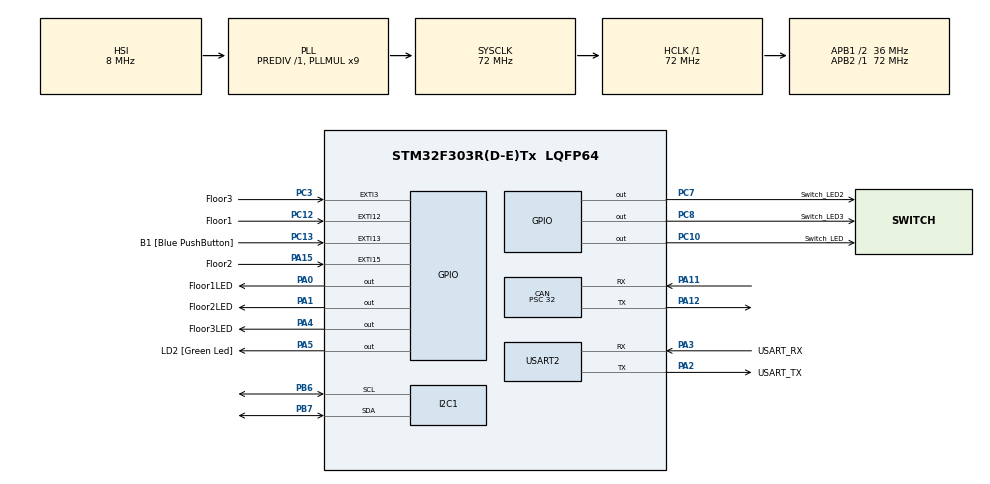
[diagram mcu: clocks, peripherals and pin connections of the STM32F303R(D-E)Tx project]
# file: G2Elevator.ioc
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CAN.BS1=CAN_BS1_4TQ
CAN.BS2=CAN_BS2_4TQ
CAN.CalculateBaudRate=125000
CAN.CalculateTimeBit=8000
CAN.CalculateTimeQuantum=888.8888888888889
CAN.Prescaler=32
Mcu.Family=STM32F3
Mcu.Name=STM32F303R(D-E)Tx
Mcu.Package=LQFP64
NVIC.EXTI15_10_IRQn=true\:0\:0\:false\:false\:true\:true\:true\:true
NVIC.PriorityGroup=NVIC_PRIORITYGROUP_0
NVIC.USB_LP_CAN_RX0_IRQn=true\:0\:0\:false\:false\:true\:true\:true\:true
PA0.GPIO_Label=Floor1LED
PA0.PinState=GPIO_PIN_RESET
PA0.Signal=GPIO_Output
PA1.GPIO_Label=Floor2LED
PA1.PinState=GPIO_PIN_RESET
PA1.Signal=GPIO_Output
PA11.Mode=CAN_Activate
PA11.Signal=CAN_RX
PA12.Mode=CAN_Activate
PA12.Signal=CAN_TX
PA13.GPIO_Label=TMS
PA13.Mode=Serial_Wire
PA13.Signal=SYS_JTMS-SWDIO
PA14.GPIO_Label=TCK
PA14.Mode=Serial_Wire
PA14.Signal=SYS_JTCK-SWCLK
PA15.GPIO_Label=Floor2
PA15.Signal=GPXTI15
PA2.GPIO_Label=USART_TX
PA2.GPIO_Mode=GPIO_MODE_AF_PP
PA2.GPIO_PuPd=GPIO_NOPULL
PA2.GPIO_Speed=GPIO_SPEED_FREQ_LOW
PA2.Mode=Asynchronous
PA2.Signal=USART2_TX
PA3.GPIO_Label=USART_RX
PA3.GPIO_Mode=GPIO_MODE_AF_PP
PA3.GPIO_PuPd=GPIO_NOPULL
PA3.GPIO_Speed=GPIO_SPEED_FREQ_LOW
PA3.Mode=Asynchronous
PA3.Signal=USART2_RX
PA4.GPIO_Label=Floor3LED
PA4.PinState=GPIO_PIN_RESET
PA4.Signal=GPIO_Output
PA5.GPIO_Label=LD2 [Green Led]
PA5.GPIO_Mode=GPIO_MODE_OUTPUT_PP
PA5.GPIO_PuPd=GPIO_NOPULL
PA5.GPIO_Speed=GPIO_SPEED_FREQ_LOW
PA5.Signal=GPIO_Output
PB3.GPIO_Label=SWO
PB3.Signal=SYS_JTDO-TRACESWO
PB6.Mode=I2C
PB6.Signal=I2C1_SCL
PB7.Mode=I2C
PB7.Signal=I2C1_SDA
PC10.GPIO_Label=Switch_LED
PC10.PinState=GPIO_PIN_RESET
PC10.Signal=GPIO_Output
PC12.GPIO_Label=Floor1
PC12.Signal=GPXTI12
PC13.GPIO_Label=B1 [Blue PushButton]
PC13.GPIO_ModeDefaultEXTI=GPIO_MODE_IT_FALLING
PC13.Signal=GPXTI13
PC14-OSC32_IN.Mode=LSE-External-Oscillator
PC14-OSC32_IN.Signal=RCC_OSC32_IN
PC15-OSC32_OUT.Mode=LSE-External-Oscillator
PC15-OSC32_OUT.Signal=RCC_OSC32_OUT
PC3.GPIO_Label=Floor3
PC3.Signal=GPXTI3
PC7.GPIO_Label=Switch_LED2
PC7.Signal=GPIO_Output
PC8.GPIO_Label=Switch_LED3
PC8.Signal=GPIO_Output
PF0-OSC_IN.Mode=HSE-External-Clock-Source
PF0-OSC_IN.Signal=RCC_OSC_IN
PF1-OSC_OUT.Signal=RCC_OSC_OUT
ProjectManager.HeapSize=0x200
ProjectManager.StackSize=0x400
ProjectManager.TargetToolchain=STM32CubeIDE
RCC.AHBFreq_Value=72000000
RCC.APB1CLKDivider=RCC_HCLK_DIV2
RCC.APB1Freq_Value=36000000
RCC.APB1TimFreq_Value=72000000
RCC.APB2Freq_Value=72000000
RCC.APB2TimFreq_Value=72000000
RCC.CortexFreq_Value=72000000
RCC.HCLKFreq_Value=72000000
RCC.HSE_VALUE=8000000
RCC.HSI_VALUE=8000000
RCC.PLLM=8
RCC.PLLMUL=RCC_PLL_MUL9
RCC.PLLN=336
RCC.PLLP=RCC_PLLP_DIV4
RCC.PLLQ=7
RCC.RCC_PLLsource_Clock_Source_FROM_HSE=RCC_HSE_PREDIV_DIV2
RCC.SYSCLKFreq_VALUE=72000000
RCC.SYSCLKSourceVirtual=RCC_SYSCLKSOURCE_PLLCLK
RCC.USBFreq_Value=72000000
USART2.VirtualMode-Asynchronous=VM_ASYNC
board=NUCLEO-F303RE

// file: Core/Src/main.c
/* USER CODE BEGIN Header */
/**
  ******************************************************************************
  * @file           : main.c
  * @brief          : Main program body
  ******************************************************************************
  * @attention
  *
  * Copyright (c) 2022 STMicroelectronics.
  * All rights reserved.
  *
  * This software is licensed under terms that can be found in the LICENSE file
  * in the root directory of this software component.
  * If no LICENSE file comes with this software, it is provided AS-IS.
  *
  ******************************************************************************
  */
/* USER CODE END Header */
#include "main.h"

/* USER CODE BEGIN PD */
#define NO_BUTTON_PRESSED 	0
#define BLUE_BUTTON_PRESSED 1

/* USER CODE END PD */

I2C_HandleTypeDef hi2c1;

UART_HandleTypeDef huart2;

/* USER CODE BEGIN PV */
//uint8_t BUTTON = NO_BUTTON_PRESSED;

/* USER CODE END PV */

void SystemClock_Config(void);
static void MX_GPIO_Init(void);
static void MX_USART2_UART_Init(void);
static void MX_CAN_Init(void);
static void MX_I2C1_Init(void);

int main(void)
{

  /* MCU Configuration--------------------------------------------------------*/

  /* Reset of all peripherals, Initializes the Flash interface and the Systick. */
  HAL_Init();

  /* Configure the system clock */
  SystemClock_Config();

  /* Initialize all configured peripherals */
  MX_GPIO_Init();
  MX_USART2_UART_Init();
  MX_CAN_Init();
  MX_I2C1_Init();

  /* Infinite loop */
  while (1)
  {

    /* USER CODE BEGIN 3 */
	  processMsg();

	  //Transmit
	  //if (BUTTON !=0) {
		  //msgTx();
	 // }
  }
  /* USER CODE END 3 */
}

void SystemClock_Config(void)
{
  RCC_OscInitTypeDef RCC_OscInitStruct = {0};
  RCC_ClkInitTypeDef RCC_ClkInitStruct = {0};
  RCC_PeriphCLKInitTypeDef PeriphClkInit = {0};

  /** Initializes the RCC Oscillators according to the specified parameters
  * in the RCC_OscInitTypeDef structure.
  */
  RCC_OscInitStruct.OscillatorType = RCC_OSCILLATORTYPE_HSI;
  RCC_OscInitStruct.HSIState = RCC_HSI_ON;
  RCC_OscInitStruct.HSICalibrationValue = RCC_HSICALIBRATION_DEFAULT;
  RCC_OscInitStruct.PLL.PLLState = RCC_PLL_ON;
  RCC_OscInitStruct.PLL.PLLSource = RCC_PLLSOURCE_HSI;
  RCC_OscInitStruct.PLL.PLLMUL = RCC_PLL_MUL9;
  RCC_OscInitStruct.PLL.PREDIV = RCC_PREDIV_DIV1;
  if (HAL_RCC_OscConfig(&RCC_OscInitStruct) != HAL_OK)
  {
    Error_Handler();
  }

  /** Initializes the CPU, AHB and APB buses clocks
  */
  RCC_ClkInitStruct.ClockType = RCC_CLOCKTYPE_HCLK|RCC_CLOCKTYPE_SYSCLK
                              |RCC_CLOCKTYPE_PCLK1|RCC_CLOCKTYPE_PCLK2;
  RCC_ClkInitStruct.SYSCLKSource = RCC_SYSCLKSOURCE_PLLCLK;
  RCC_ClkInitStruct.AHBCLKDivider = RCC_SYSCLK_DIV1;
  RCC_ClkInitStruct.APB1CLKDivider = RCC_HCLK_DIV2;
  RCC_ClkInitStruct.APB2CLKDivider = RCC_HCLK_DIV1;

  if (HAL_RCC_ClockConfig(&RCC_ClkInitStruct, FLASH_LATENCY_2) != HAL_OK)
  {
    Error_Handler();
  }
  PeriphClkInit.PeriphClockSelection = RCC_PERIPHCLK_USART2|RCC_PERIPHCLK_I2C1;
  PeriphClkInit.Usart2ClockSelection = RCC_USART2CLKSOURCE_PCLK1;
  PeriphClkInit.I2c1ClockSelection = RCC_I2C1CLKSOURCE_HSI;
  if (HAL_RCCEx_PeriphCLKConfig(&PeriphClkInit) != HAL_OK)
  {
    Error_Handler();
  }
}

static void MX_CAN_Init(void)
{

  canInit();

  /* USER CODE END CAN_Init 2 */

}

static void MX_I2C1_Init(void)
{

  hi2c1.Instance = I2C1;
  hi2c1.Init.Timing = 0x2000090E;
  hi2c1.Init.OwnAddress1 = 0;
  hi2c1.Init.AddressingMode = I2C_ADDRESSINGMODE_7BIT;
  hi2c1.Init.DualAddressMode = I2C_DUALADDRESS_DISABLE;
  hi2c1.Init.OwnAddress2 = 0;
  hi2c1.Init.OwnAddress2Masks = I2C_OA2_NOMASK;
  hi2c1.Init.GeneralCallMode = I2C_GENERALCALL_DISABLE;
  hi2c1.Init.NoStretchMode = I2C_NOSTRETCH_DISABLE;
  if (HAL_I2C_Init(&hi2c1) != HAL_OK)
  {
    Error_Handler();
  }

  /** Configure Analogue filter
  */
  if (HAL_I2CEx_ConfigAnalogFilter(&hi2c1, I2C_ANALOGFILTER_ENABLE) != HAL_OK)
  {
    Error_Handler();
  }

  /** Configure Digital filter
  */
  if (HAL_I2CEx_ConfigDigitalFilter(&hi2c1, 0) != HAL_OK)
  {
    Error_Handler();
  }

}

static void MX_USART2_UART_Init(void)
{

  huart2.Instance = USART2;
  huart2.Init.BaudRate = 38400;
  huart2.Init.WordLength = UART_WORDLENGTH_8B;
  huart2.Init.StopBits = UART_STOPBITS_1;
  huart2.Init.Parity = UART_PARITY_NONE;
  huart2.Init.Mode = UART_MODE_TX_RX;
  huart2.Init.HwFlowCtl = UART_HWCONTROL_NONE;
  huart2.Init.OverSampling = UART_OVERSAMPLING_16;
  huart2.Init.OneBitSampling = UART_ONE_BIT_SAMPLE_DISABLE;
  huart2.AdvancedInit.AdvFeatureInit = UART_ADVFEATURE_NO_INIT;
  if (HAL_UART_Init(&huart2) != HAL_OK)
  {
    Error_Handler();
  }

}

static void MX_GPIO_Init(void)
{
  GPIO_InitTypeDef GPIO_InitStruct = {0};

  /* GPIO Ports Clock Enable */
  __HAL_RCC_GPIOC_CLK_ENABLE();
  __HAL_RCC_GPIOF_CLK_ENABLE();
  __HAL_RCC_GPIOA_CLK_ENABLE();
  __HAL_RCC_GPIOB_CLK_ENABLE();

  /*Configure GPIO pin Output Level */
  HAL_GPIO_WritePin(GPIOC, Debounce2_Pin|Switch_LED2_Pin|Switch_LED3_Pin|Switch_LED_Pin, GPIO_PIN_RESET);

  /*Configure GPIO pin Output Level */
  HAL_GPIO_WritePin(GPIOA, Floor1LED_Pin|Floor2LED_Pin|Floor3LED_Pin|LD2_Pin
                          |Debouce1_Pin, GPIO_PIN_RESET);

  /*Configure GPIO pin : B1_Pin */
  GPIO_InitStruct.Pin = B1_Pin;
  GPIO_InitStruct.Mode = GPIO_MODE_IT_FALLING;
  GPIO_InitStruct.Pull = GPIO_NOPULL;
  HAL_GPIO_Init(B1_GPIO_Port, &GPIO_InitStruct);

  /*Configure GPIO pins : Debounce2_Pin Switch_LED2_Pin Switch_LED3_Pin Switch_LED_Pin */
  GPIO_InitStruct.Pin = Debounce2_Pin|Switch_LED2_Pin|Switch_LED3_Pin|Switch_LED_Pin;
  GPIO_InitStruct.Mode = GPIO_MODE_OUTPUT_PP;
  GPIO_InitStruct.Pull = GPIO_NOPULL;
  GPIO_InitStruct.Speed = GPIO_SPEED_FREQ_LOW;
  HAL_GPIO_Init(GPIOC, &GPIO_InitStruct);

  /*Configure GPIO pins : Floor1LED_Pin Floor2LED_Pin Floor3LED_Pin LD2_Pin
                           Debouce1_Pin */
  GPIO_InitStruct.Pin = Floor1LED_Pin|Floor2LED_Pin|Floor3LED_Pin|LD2_Pin
                          |Debouce1_Pin;
  GPIO_InitStruct.Mode = GPIO_MODE_OUTPUT_PP;
  GPIO_InitStruct.Pull = GPIO_NOPULL;
  GPIO_InitStruct.Speed = GPIO_SPEED_FREQ_LOW;
  HAL_GPIO_Init(GPIOA, &GPIO_InitStruct);

  /*Configure GPIO pin : Floor_switch_Pin */
  GPIO_InitStruct.Pin = Floor_switch_Pin;
  GPIO_InitStruct.Mode = GPIO_MODE_INPUT;
  GPIO_InitStruct.Pull = GPIO_NOPULL;
  HAL_GPIO_Init(Floor_switch_GPIO_Port, &GPIO_InitStruct);

  /* EXTI interrupt init*/
  HAL_NVIC_SetPriority(EXTI15_10_IRQn, 0, 0);
  HAL_NVIC_EnableIRQ(EXTI15_10_IRQn);

}

void Error_Handler(void)
{
  __disable_irq();
  while (1)
  {
  }
}
